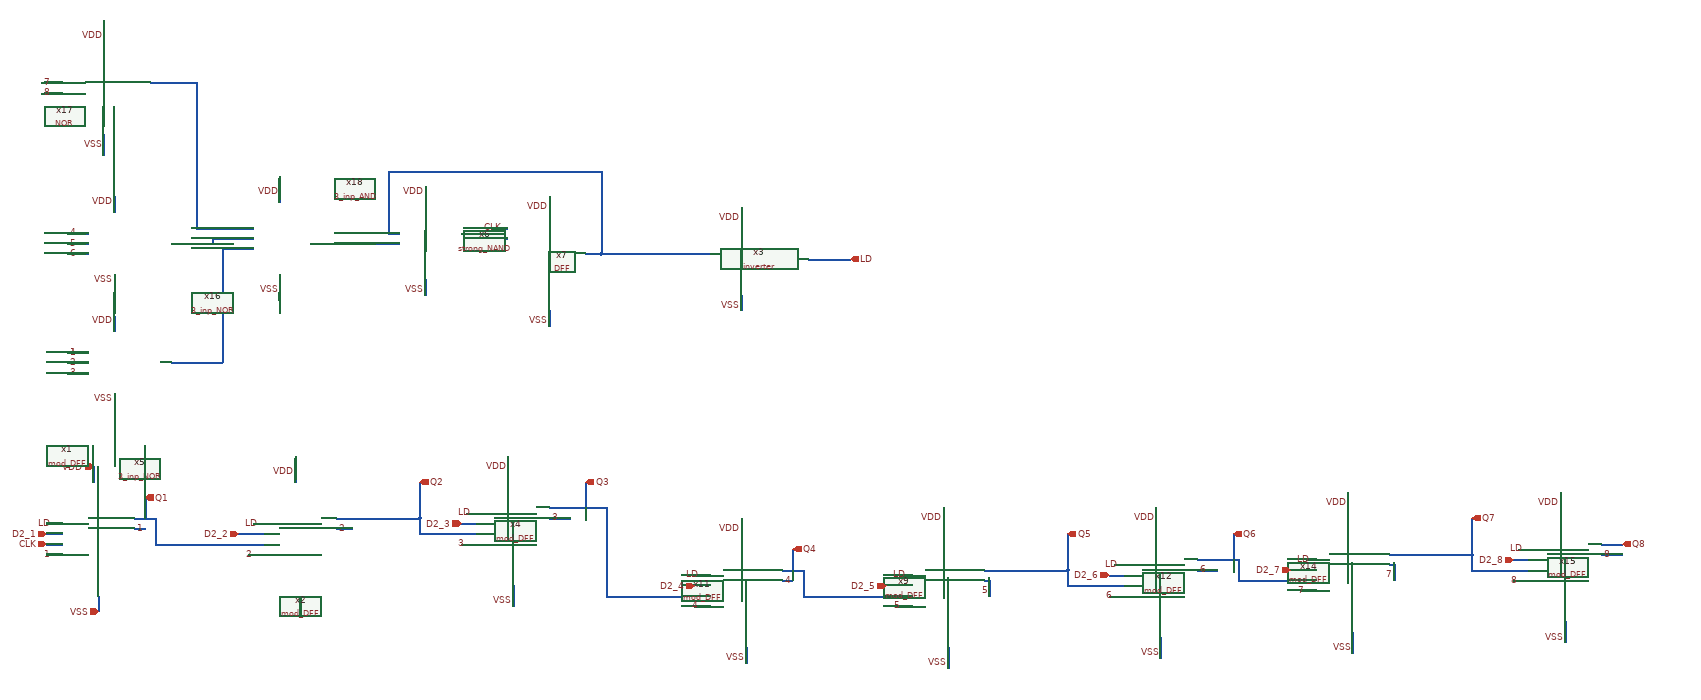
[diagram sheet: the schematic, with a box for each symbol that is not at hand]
v {xschem version=3.1.0 file_version=1.2
}
G {}
K {}
V {}
S {}
E {}
N 630 850 650 850 {
lab=1}
N 460 900 490 900 {
lab=1}
N 460 860 490 860 {
lab=D2_1}
N 460 880 490 880 {
lab=CLK}
N 560 980 560 1010 {
lab=VSS}
N 660 830 670 830 {
lab=Q1}
N 670 830 670 870 {
lab=Q1}
N 840 880 880 880 {
lab=Q1}
N 1970 330 2010 330 {
lab=LD}
N 460 840 490 840 {
lab=LD}
N 860 840 880 840 {
lab=LD}
N 500 510 540 510 {
lab=1}
N 500 530 540 530 {
lab=2}
N 500 550 540 550 {
lab=3}
N 590 440 590 470 {
lab=VDD}
N 590 590 590 610 {
lab=VSS}
N 1530 160 1530 320 {
lab=#net1}
N 1120 160 1530 160 {
lab=#net1}
N 1120 160 1120 280 {
lab=#net1}
N 1120 280 1140 280 {
lab=#net1}
N 1530 320 1590 320 {
lab=#net1}
N 1430 210 1430 240 {
lab=VDD}
N 1190 190 1190 220 {
lab=VDD}
N 1190 370 1190 400 {
lab=VSS}
N 1800 230 1800 260 {
lab=VDD}
N 940 710 940 760 {
lab=VDD}
N 1250 860 1290 860 {
lab=Q2}
N 1430 830 1470 830 {
lab=3}
N 860 860 880 860 {
lab=D2_2}
N 650 790 650 830 {
lab=Q1}
N 1180 760 1180 810 {
lab=Q2}
N 1430 810 1470 810 {
lab=Q3}
N 830 860 860 860 {
lab=D2_2}
N 1350 710 1350 740 {
lab=VDD}
N 1360 960 1360 1000 {
lab=VSS}
N 1260 840 1290 840 {
lab=D2_3}
N 850 900 880 900 {
lab=2}
N 1260 880 1290 880 {
lab=3}
N 1320 270 1350 270 {
lab=CLK}
N 1270 820 1290 820 {
lab=LD}
N 1180 810 1180 820 {
lab=Q2}
N 1590 320 1740 320 {
lab=#net1}
N 670 870 670 880 {
lab=Q1}
N 670 880 840 880 {
lab=Q1}
N 1180 820 1180 830 {
lab=Q2}
N 1180 830 1180 860 {
lab=Q2}
N 1180 860 1250 860 {
lab=Q2}
N 1270 290 1350 290 {
lab=#net2}
N 1800 400 1800 430 {
lab=VSS}
N 950 980 950 1020 {
lab=VSS}
N 1880 950 1900 950 {
lab=4}
N 1710 1000 1740 1000 {
lab=4}
N 1710 960 1740 960 {
lab=D2_4}
N 1710 980 1740 980 {
lab=Q3}
N 1800 830 1800 860 {
lab=VDD}
N 1810 1080 1810 1110 {
lab=VSS}
N 1880 930 1910 930 {
lab=Q4}
N 1910 930 1920 930 {
lab=Q4}
N 1920 930 1920 970 {
lab=Q4}
N 2090 980 2130 980 {
lab=Q4}
N 1710 940 1740 940 {
lab=LD}
N 2110 940 2130 940 {
lab=LD}
N 2190 810 2190 860 {
lab=VDD}
N 2500 960 2540 960 {
lab=Q5}
N 2680 930 2720 930 {
lab=6}
N 2270 950 2280 950 {
lab=5}
N 2280 950 2280 980 {
lab=5}
N 2110 960 2130 960 {
lab=D2_5}
N 1900 890 1900 930 {
lab=Q4}
N 2430 860 2430 910 {
lab=Q5}
N 2680 910 2720 910 {
lab=Q6}
N 2080 960 2110 960 {
lab=D2_5}
N 2600 810 2600 840 {
lab=VDD}
N 2610 1060 2610 1100 {
lab=VSS}
N 2510 940 2540 940 {
lab=D2_6}
N 2100 1000 2130 1000 {
lab=5}
N 2510 980 2540 980 {
lab=6}
N 2520 920 2540 920 {
lab=LD}
N 2430 910 2430 920 {
lab=Q5}
N 1920 970 1920 980 {
lab=Q4}
N 1920 980 2090 980 {
lab=Q4}
N 2270 930 2430 930 {
lab=Q5}
N 2430 920 2430 930 {
lab=Q5}
N 2430 930 2430 960 {
lab=Q5}
N 2200 1080 2200 1120 {
lab=VSS}
N 1470 810 1540 810 {
lab=Q3}
N 1540 810 1540 980 {
lab=Q3}
N 1540 980 1710 980 {
lab=Q3}
N 1500 760 1500 810 {
lab=Q3}
N 2870 950 2910 950 {
lab=Q6}
N 2890 910 2910 910 {
lab=LD}
N 2970 780 2970 830 {
lab=VDD}
N 3280 930 3320 930 {
lab=Q7}
N 3460 900 3500 900 {
lab=8}
N 3050 920 3060 920 {
lab=7}
N 3060 920 3060 950 {
lab=7}
N 2890 930 2910 930 {
lab=D2_7}
N 3210 830 3210 880 {
lab=Q7}
N 3460 880 3500 880 {
lab=Q8}
N 2860 930 2890 930 {
lab=D2_7}
N 3380 780 3380 810 {
lab=VDD}
N 3390 1030 3390 1070 {
lab=VSS}
N 3290 910 3320 910 {
lab=D2_8}
N 2880 970 2910 970 {
lab=7}
N 3290 950 3320 950 {
lab=8}
N 3300 890 3320 890 {
lab=LD}
N 3210 880 3210 890 {
lab=Q7}
N 3050 900 3210 900 {
lab=Q7}
N 3210 890 3210 900 {
lab=Q7}
N 3210 900 3210 930 {
lab=Q7}
N 2980 1050 2980 1090 {
lab=VSS}
N 2720 910 2760 910 {
lab=Q6}
N 2760 910 2760 950 {
lab=Q6}
N 2750 860 2750 910 {
lab=Q6}
N 500 280 540 280 {
lab=4}
N 500 300 540 300 {
lab=5}
N 500 320 540 320 {
lab=6}
N 590 210 590 240 {
lab=VDD}
N 590 360 590 380 {
lab=VSS}
N 450 -10 490 -10 {
lab=7}
N 450 10 490 10 {
lab=8}
N 570 -130 570 -90 {
lab=VDD}
N 570 90 570 130 {
lab=VSS}
N 700 530 800 530 {
lab=#net3}
N 800 310 800 530 {
lab=#net3}
N 800 310 860 310 {
lab=#net3}
N 700 300 780 300 {
lab=#net4}
N 780 290 780 300 {
lab=#net4}
N 780 290 860 290 {
lab=#net4}
N 660 -10 750 -10 {
lab=#net5}
N 750 -10 750 270 {
lab=#net5}
N 750 270 860 270 {
lab=#net5}
N 910 170 910 220 {
lab=VDD}
N 910 360 910 410 {
lab=VSS}
N 970 300 1140 300 {
lab=#net6}
N 1500 320 1530 320 {
lab=#net1}
N 1430 430 1430 460 {
lab=VSS}
N 1020 850 1050 850 {
lab=2}
N 2430 960 2500 960 {
lab=Q5}
N 2760 950 2870 950 {
lab=Q6}
N 640 830 660 830 {
lab=Q1}
N 1020 830 1180 830 {
lab=Q2}
N 550 730 550 760 {
lab=VDD}
N 630 830 640 830 {
lab=Q1}
N 3210 930 3280 930 {
lab=Q7}
N 1260 280 1270 280 {
lab=#net2}
N 1270 280 1270 290 {
lab=#net2}
N 1930 330 1970 330 {
lab=LD}
C {mod_DFF.sym} 1440 850 0 0 {name=x4}
C {3_inp_NOR.sym} 910 630 0 0 {name=x5}
C {devices/lab_wire.sym} 470 840 0 0 {name=p2 sig_type=std_logic lab=LD}
C {devices/lab_wire.sym} 870 840 0 0 {name=p3 sig_type=std_logic lab=LD}
C {devices/iopin.sym} 550 730 3 0 {name=p4 lab=VDD}
C {devices/iopin.sym} 560 1010 1 0 {name=p5 lab=VSS}
C {devices/lab_wire.sym} 590 450 0 0 {name=p6 sig_type=std_logic lab=VDD}
C {devices/lab_wire.sym} 590 600 0 0 {name=p7 sig_type=std_logic lab=VSS}
C {devices/lab_wire.sym} 1190 200 0 0 {name=p8 sig_type=std_logic lab=VDD}
C {devices/lab_wire.sym} 1430 230 0 0 {name=p9 sig_type=std_logic lab=VDD}
C {devices/lab_wire.sym} 1800 250 0 0 {name=p10 sig_type=std_logic lab=VDD}
C {devices/lab_wire.sym} 940 740 0 0 {name=p11 sig_type=std_logic lab=VDD}
C {devices/lab_wire.sym} 1190 390 0 0 {name=p12 sig_type=std_logic lab=VSS}
C {devices/lab_wire.sym} 1800 420 0 0 {name=p14 sig_type=std_logic lab=VSS}
C {devices/lab_wire.sym} 950 1010 0 0 {name=p15 sig_type=std_logic lab=VSS}
C {devices/opin.sym} 1500 760 3 0 {name=p16 lab=Q3}
C {devices/opin.sym} 650 790 3 0 {name=p17 lab=Q1}
C {devices/ipin.sym} 460 860 0 0 {name=p18 lab=D2_1}
C {devices/ipin.sym} 830 860 0 0 {name=p19 lab=D2_2}
C {devices/lab_wire.sym} 1350 730 0 0 {name=p22 sig_type=std_logic lab=VDD}
C {devices/lab_wire.sym} 1360 990 0 0 {name=p23 sig_type=std_logic lab=VSS}
C {devices/ipin.sym} 1260 840 0 0 {name=p24 lab=D2_3}
C {devices/lab_wire.sym} 520 510 0 0 {name=p27 sig_type=std_logic lab=1}
C {devices/lab_wire.sym} 520 530 0 0 {name=p28 sig_type=std_logic lab=2}
C {devices/lab_wire.sym} 520 510 0 0 {name=p29 sig_type=std_logic lab=1}
C {devices/lab_wire.sym} 520 550 0 0 {name=p30 sig_type=std_logic lab=3}
C {devices/lab_wire.sym} 650 850 0 0 {name=p31 sig_type=std_logic lab=1}
C {devices/lab_wire.sym} 470 900 0 0 {name=p32 sig_type=std_logic lab=1}
C {devices/lab_wire.sym} 860 900 0 0 {name=p33 sig_type=std_logic lab=2}
C {devices/lab_wire.sym} 1040 850 0 0 {name=p34 sig_type=std_logic lab=2}
C {devices/lab_wire.sym} 1450 830 0 0 {name=p35 sig_type=std_logic lab=3}
C {devices/lab_wire.sym} 1270 880 0 0 {name=p36 sig_type=std_logic lab=3}
C {devices/ipin.sym} 460 880 0 0 {name=p37 lab=CLK}
C {devices/lab_wire.sym} 1340 270 0 0 {name=p38 sig_type=std_logic lab=CLK}
C {devices/opin.sym} 1180 760 3 0 {name=p39 lab=Q2}
C {devices/lab_wire.sym} 1280 820 0 0 {name=p40 sig_type=std_logic lab=LD}
C {devices/opin.sym} 2010 330 0 0 {name=p41 lab=LD}
C {mod_DFF.sym} 2280 970 0 0 {name=x9}
C {mod_DFF.sym} 1890 970 0 0 {name=x11}
C {mod_DFF.sym} 2690 950 0 0 {name=x12}
C {devices/lab_wire.sym} 1720 940 0 0 {name=p1 sig_type=std_logic lab=LD}
C {devices/lab_wire.sym} 2120 940 0 0 {name=p20 sig_type=std_logic lab=LD}
C {devices/lab_wire.sym} 2190 830 0 0 {name=p26 sig_type=std_logic lab=VDD}
C {devices/lab_wire.sym} 2200 1110 0 0 {name=p42 sig_type=std_logic lab=VSS}
C {devices/opin.sym} 2750 860 3 0 {name=p43 lab=Q6}
C {devices/opin.sym} 1900 890 3 0 {name=p44 lab=Q4}
C {devices/ipin.sym} 1710 960 0 0 {name=p45 lab=D2_4}
C {devices/ipin.sym} 2080 960 0 0 {name=p46 lab=D2_5}
C {devices/lab_wire.sym} 2600 830 0 0 {name=p47 sig_type=std_logic lab=VDD}
C {devices/lab_wire.sym} 2610 1090 0 0 {name=p48 sig_type=std_logic lab=VSS}
C {devices/ipin.sym} 2510 940 0 0 {name=p49 lab=D2_6}
C {devices/lab_wire.sym} 1900 950 0 0 {name=p50 sig_type=std_logic lab=4}
C {devices/lab_wire.sym} 1720 1000 0 0 {name=p51 sig_type=std_logic lab=4}
C {devices/lab_wire.sym} 2110 1000 0 0 {name=p52 sig_type=std_logic lab=5}
C {devices/lab_wire.sym} 2700 930 0 0 {name=p54 sig_type=std_logic lab=6}
C {devices/lab_wire.sym} 2520 980 0 0 {name=p55 sig_type=std_logic lab=6}
C {devices/opin.sym} 2430 860 3 0 {name=p57 lab=Q5}
C {devices/lab_wire.sym} 2530 920 0 0 {name=p58 sig_type=std_logic lab=LD}
C {devices/lab_wire.sym} 2280 970 0 0 {name=p53 sig_type=std_logic lab=5}
C {mod_DFF.sym} 3060 940 0 0 {name=x14}
C {mod_DFF.sym} 3470 920 0 0 {name=x15}
C {devices/lab_wire.sym} 2900 910 0 0 {name=p56 sig_type=std_logic lab=LD}
C {devices/lab_wire.sym} 2970 800 0 0 {name=p59 sig_type=std_logic lab=VDD}
C {devices/lab_wire.sym} 2980 1080 0 0 {name=p60 sig_type=std_logic lab=VSS}
C {devices/ipin.sym} 2860 930 0 0 {name=p61 lab=D2_7}
C {devices/lab_wire.sym} 3380 800 0 0 {name=p62 sig_type=std_logic lab=VDD}
C {devices/lab_wire.sym} 3390 1060 0 0 {name=p63 sig_type=std_logic lab=VSS}
C {devices/ipin.sym} 3290 910 0 0 {name=p64 lab=D2_8}
C {devices/lab_wire.sym} 2890 970 0 0 {name=p65 sig_type=std_logic lab=7}
C {devices/lab_wire.sym} 3480 900 0 0 {name=p66 sig_type=std_logic lab=8}
C {devices/lab_wire.sym} 3300 950 0 0 {name=p67 sig_type=std_logic lab=8}
C {devices/opin.sym} 3210 830 3 0 {name=p68 lab=Q7}
C {devices/lab_wire.sym} 3310 890 0 0 {name=p69 sig_type=std_logic lab=LD}
C {devices/lab_wire.sym} 3060 940 0 0 {name=p70 sig_type=std_logic lab=7}
C {devices/opin.sym} 3500 880 0 0 {name=p71 lab=Q8}
C {3_inp_NOR.sym} 910 400 0 0 {name=x16}
C {devices/lab_wire.sym} 590 220 0 0 {name=p72 sig_type=std_logic lab=VDD}
C {devices/lab_wire.sym} 590 370 0 0 {name=p73 sig_type=std_logic lab=VSS}
C {devices/lab_wire.sym} 520 300 0 0 {name=p75 sig_type=std_logic lab=5}
C {devices/lab_wire.sym} 520 280 0 0 {name=p76 sig_type=std_logic lab=4}
C {devices/lab_wire.sym} 520 320 0 0 {name=p77 sig_type=std_logic lab=6}
C {NOR.sym} 640 10 0 0 {name=x17}
C {devices/lab_wire.sym} 570 -100 0 0 {name=p74 sig_type=std_logic lab=VDD}
C {devices/lab_wire.sym} 570 110 0 0 {name=p78 sig_type=std_logic lab=VSS}
C {devices/lab_wire.sym} 470 -10 0 0 {name=p79 sig_type=std_logic lab=7}
C {devices/lab_wire.sym} 470 10 0 0 {name=p80 sig_type=std_logic lab=8}
C {3_inp_AND.sym} 1010 290 0 0 {name=x18}
C {devices/lab_wire.sym} 910 200 0 0 {name=p81 sig_type=std_logic lab=VDD}
C {devices/lab_wire.sym} 910 390 0 0 {name=p82 sig_type=std_logic lab=VSS}
C {DFF.sym} 1500 290 0 0 {name=x7}
C {devices/lab_wire.sym} 1430 450 0 0 {name=p83 sig_type=std_logic lab=VSS}
C {devices/lab_wire.sym} 1800 850 0 0 {name=p21 sig_type=std_logic lab=VDD}
C {devices/lab_wire.sym} 1810 1100 0 0 {name=p25 sig_type=std_logic lab=VSS}
C {mod_DFF.sym} 1030 870 0 0 {name=x2}
C {mod_DFF.sym} 640 870 0 0 {name=x1}
C {strong_NAND.sym} 1290 300 0 0 {name=x6}
C {inverter.sym} 1890 340 0 0 {name=x3}
